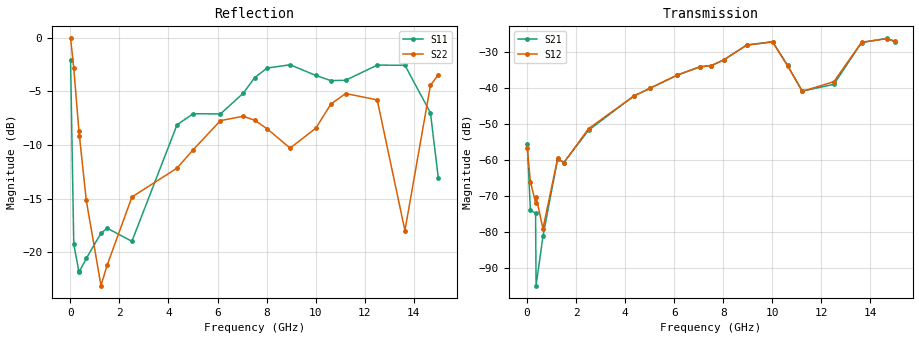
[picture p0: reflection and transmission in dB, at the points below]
!Agilent Technologies,N5230A,MY45001650,A.07.50.48
!Agilent N5230A: A.07.50.48
!Date: Wednesday, April 30, 2014 16:48:10
!Correction: S11(Full 2 Port(1,2))
!S21(Full 2 Port(1,2))
!S12(Full 2 Port(1,2))
!S22(Full 2 Port(1,2))
!S2P File: Measurements: S11, S21, S12, S22:
# Hz S  dB  R 50
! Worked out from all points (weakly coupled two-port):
!   1500 points, 10 MHz to 15 GHz, reference 50 ohm
!   highest |S21| = -26.24 dB at 14.68 GHz (marker M1); lowest = -94.9 dB at 370 MHz (marker M2)
!   lowest |S11| = -21.8 dB at 350 MHz (marker M3), VSWR 1.18, Z = 56.7 - j5.47 ohm
!   |S11| at or under -10 dB: 38.77 MHz to 3.927 GHz (3.888 GHz wide, 196 % of centre); 14.83 GHz to end of sweep
!   |S22| runs from -23.3 to -0.1 dB; largest |S21 - S12| = 0.0026
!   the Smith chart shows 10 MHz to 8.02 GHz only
!   S11 on the Smith chart (normalised r, x): 10 MHz: 1.14, -2.69; 1.5 GHz: 0.95, -0.25; 4.35 GHz: 2.14, -0.51; 6.12 GHz: 0.45, -0.36; 7.05 GHz: 0.37, +0.50; 8.02 GHz: 0.95, +2.03
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1e7  -2.12 -35.5  -55.68 2.6  -56.78 10.4  -0.08 -4.5
1.4e8  -19.21 -52.7  -73.98 109.9  -66.05 33.5  -2.85 -52.2
3.5e8  -21.80 -36.1  -74.79 0.1  -71.87 159.0  -8.69 -94.1
3.7e8  -21.76 -35.8  -94.91 -54.8  -70.17 -146.3  -9.14 -97.0
6.5e8  -20.56 -41.2  -81.23 -68.8  -79.10 145.8  -15.15 -133.0
1.25e9  -18.20 -76.4  -59.65 116.3  -59.54 107.1  -23.09 118.0
1.5e9  -17.74 -94.4  -60.72 74.5  -60.78 80.4  -21.19 76.4
2.51e9  -18.96 -172.4  -51.75 23.2  -51.29 21.2  -14.84 -0.1
4.35e9  -8.12 -15.0  -42.26 -103.0  -42.28 -102.8  -12.15 -106.3
5.01e9  -7.09 -53.1  -40.09 -145.8  -40.15 -145.9  -10.44 -148.8
6.12e9  -7.11 -132.5  -36.49 137.1  -36.41 136.4  -7.73 156.0
7.05e9  -5.18 121.6  -34.12 59.6  -34.17 60.0  -7.33 117.3
7.51e9  -3.75 80.1  -33.79 23.9  -33.85 23.3  -7.69 96.9
8.02e9  -2.84 45.3  -32.22 -12.1  -32.24 -11.7  -8.49 71.3
8.96e9  -2.54 -5.5  -28.08 -105.0  -28.10 -105.6  -10.29 13.3
1.001e10  -3.53 -67.6  -27.17 116.8  -27.27 117.0  -8.43 -48.4
1.062e10  -4.01 -117.9  -33.71 39.3  -33.83 40.4  -6.20 -86.5
1.122e10  -3.98 177.7  -40.88 -3.0  -40.94 -2.2  -5.21 -116.3
1.251e10  -2.57 71.2  -39.00 -46.5  -38.27 -49.6  -5.80 -159.3
1.364e10  -2.58 28.9  -27.39 -176.8  -27.31 -177.7  -17.96 83.9
1.468e10  -7.01 -41.6  -26.24 59.8  -26.32 60.4  -4.45 -25.7
1.5e10  -13.04 -124.5  -27.27 17.4  -26.99 18.4  -3.47 -31.0
